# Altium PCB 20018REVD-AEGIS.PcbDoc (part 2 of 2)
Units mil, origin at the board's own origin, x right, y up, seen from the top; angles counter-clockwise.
Board outline 3400 x 2150 mil, 4 copper layers (Top Layer, Signal Layer 1, Signal Layer 2, Bottom Layer), stack 66.258 mil thick; 182 components, 126 nets, 668 pads, 320 vias.

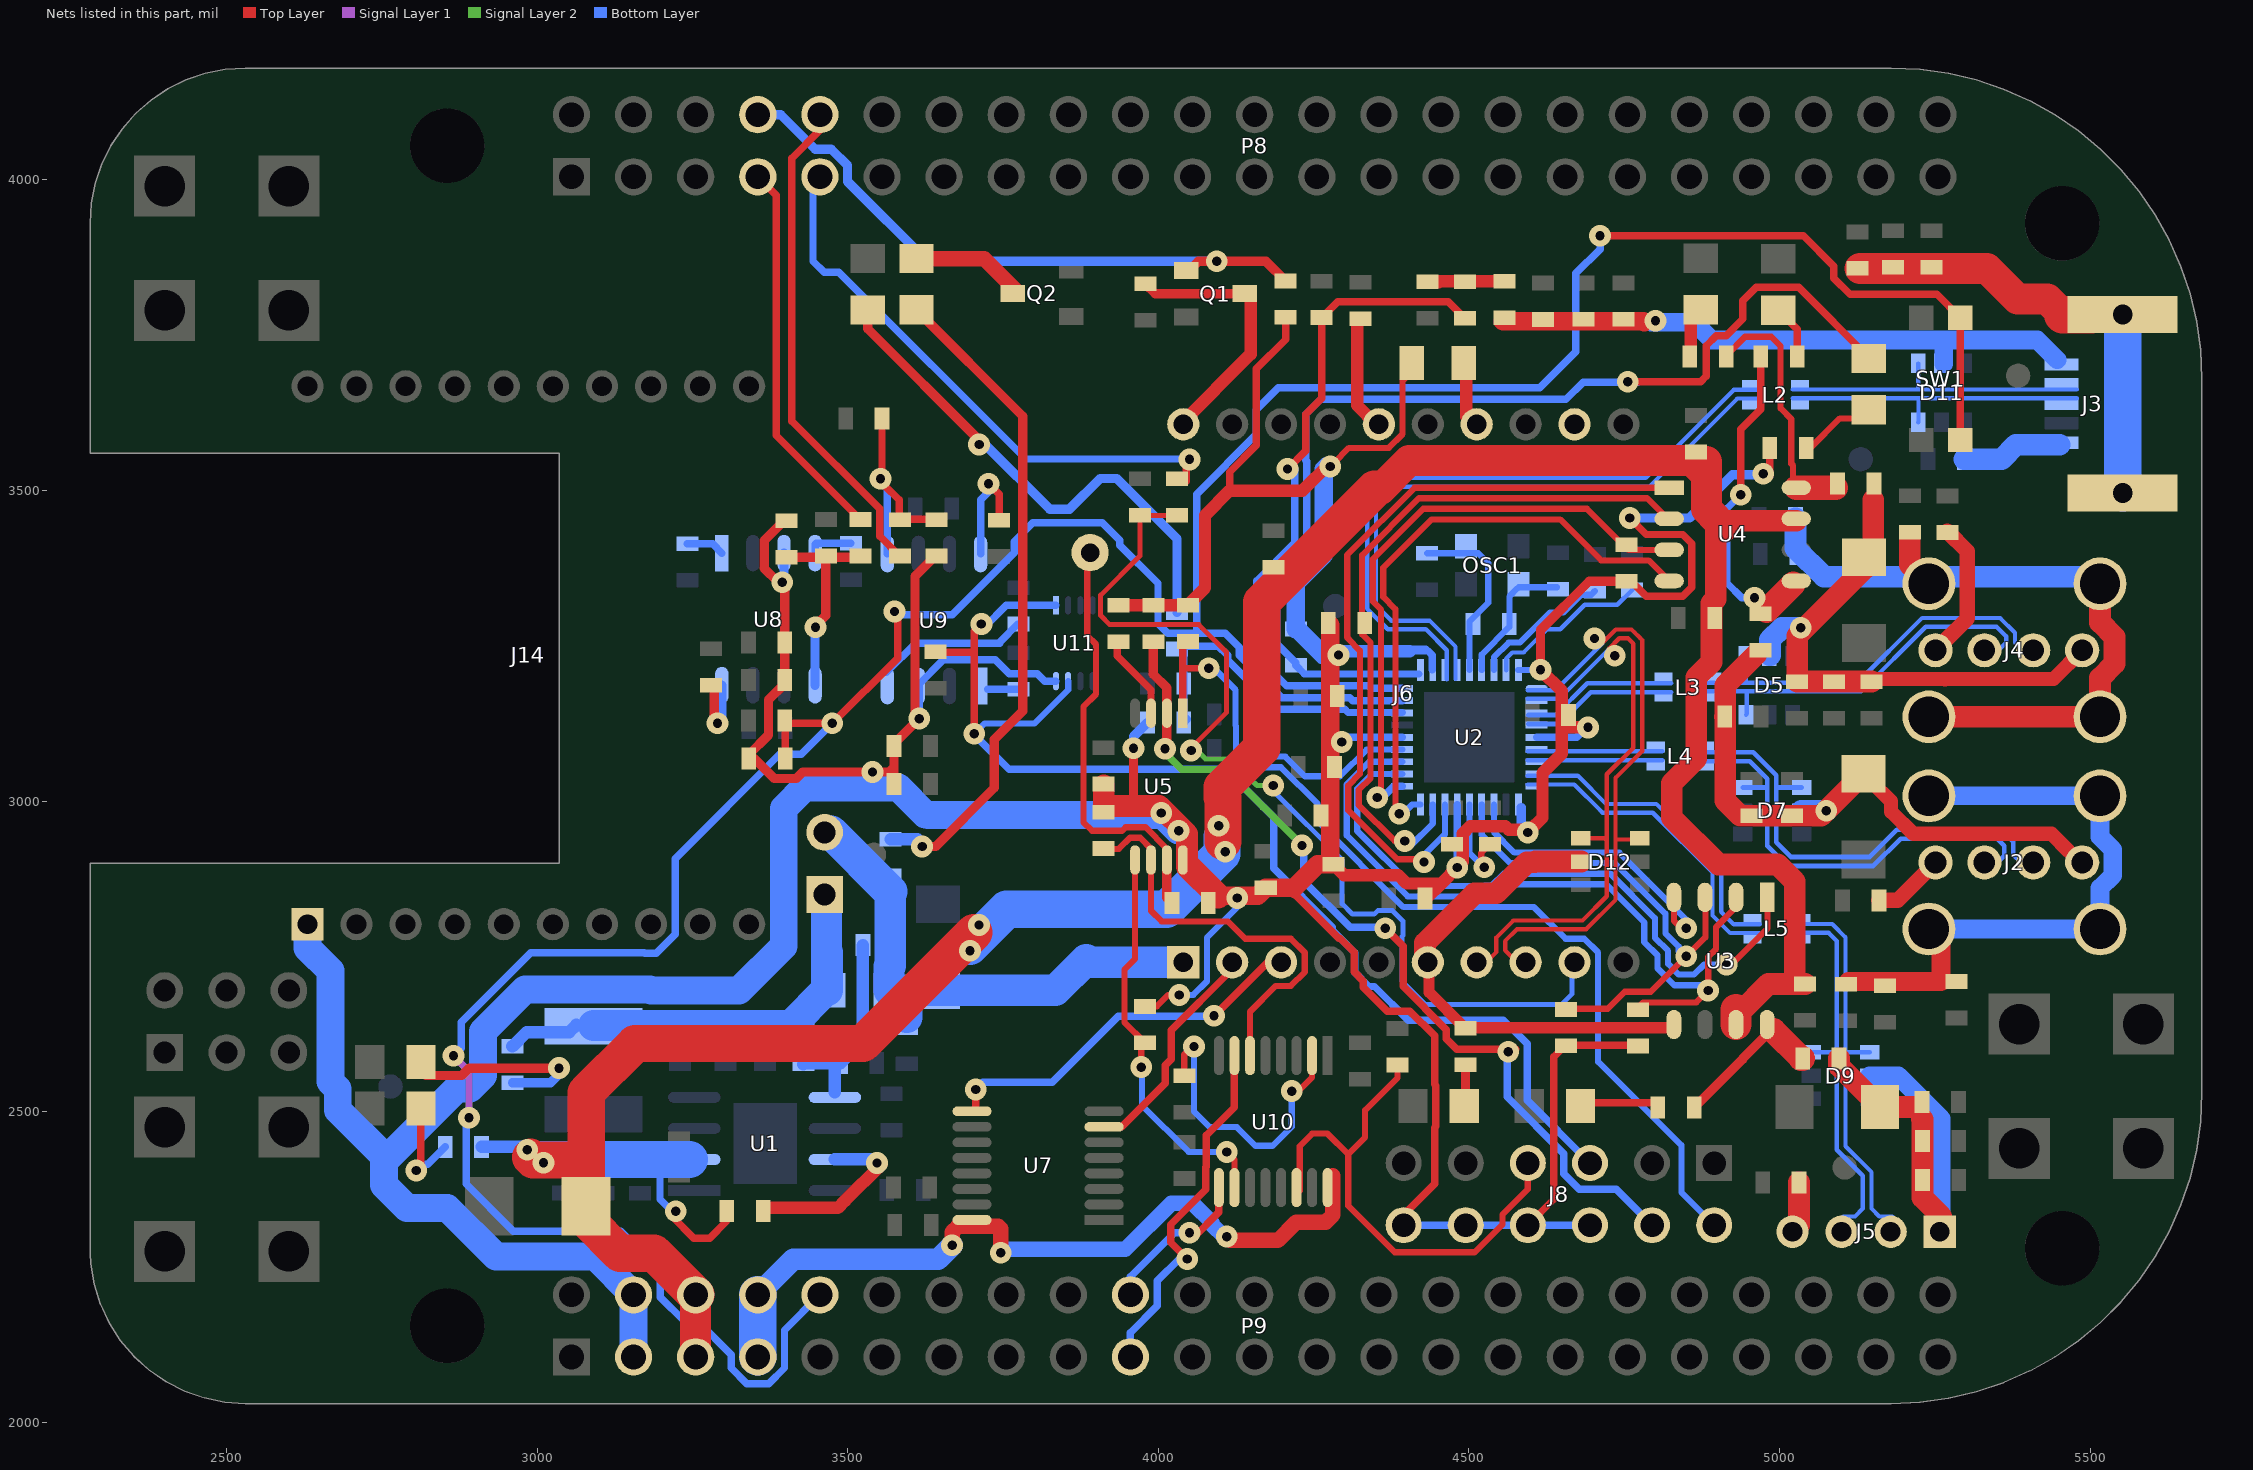
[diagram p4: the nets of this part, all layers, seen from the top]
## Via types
v1: diameter 35, hole 15, Top Layer to Bottom Layer, 320 vias

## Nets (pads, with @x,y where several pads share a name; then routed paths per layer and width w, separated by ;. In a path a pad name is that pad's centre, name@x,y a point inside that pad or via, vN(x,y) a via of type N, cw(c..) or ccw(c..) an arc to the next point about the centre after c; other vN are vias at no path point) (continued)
NetC7_2: C7.2 R5.1 R6.2 U1.5 | length 303.6
  Bottom Layer w20: C7.2@3428.31,2576.21 3430.08,2577.98 3479.22,2577.98 U1.5@3479.22,2530.92 ; R6.2@3488.09,2577.98 3523.88,2613.78 3523.88,2767.32 R5.1@3524.41,2767.85
NetC12_1: C12.1 U2.34 | length 227.7
  Bottom Layer w10: U2.34@4540.09,3210.78 4540.09,3231.41 4563.68,3255 4582.07,3255 4630.4,3303.33 4651.87,3303.33 4680.6,3332.06 4696.73,3332.06 C12.1@4702.89,3338.23
NetC13_1: C13.1 U2.14 | length 145.9
  Top Layer w10: v1@4519.61,2899.36 4519.61,2916.44 C13.1@4533.76,2930.58
  Bottom Layer w10: U2.14@4500.72,2994.25 4500.72,2916.53 v1@4522.72,2894.53
  other v1: 4524.79,2893.49
NetC14_2: C14.2 OSC1.1 R40.2 U2.33 | length 219.8
  Bottom Layer w10: U2.33@4520.4,3210.78 4520.4,3235.77 4565.04,3280.4 4565.04,3329.27 4578.08,3342.31 4580.03,3344.26 C14.2@4641.64,3344.26
NetC15_1: C15.1 FB9.2 J3.6 R19.2 | length 690.1
  Top Layer w50: C15.1@5129.88,3857.56 5333.83,3857.56 5383.4,3808 5431.04,3808 5456.13,3782.91
  Top Layer w60: 5456.13,3782.91 J3.6@5501.66,3782.91
  Bottom Layer w60: J3.6@5552.5,3496.03 J3.6@5552.5,3783.43
NetC16_2: C16.2 OSC1.3 R40.1 U2.32 | length 289.5
  Bottom Layer w10: C16.2@4432.71,3399 4432.86,3398.85 4514.88,3398.85 4531.01,3382.72 4531.01,3319.28 4500.72,3288.99 U2.32@4500.72,3210.78
NetC17_1: C17.1 P9.10 R55.1 SW1.1 SW1.3 U2.26 | length 5392.3
  Top Layer w12: C17.1@3398.62,3130 3399.17,3129.45 R55.1@3399.17,3068.43 ; C17.1@3403.62,3125 v1(3475,3125) 3580,3230 v1@3580,3305 ; v1@4713.71,3910.42 5038.04,3910.42 5087.26,3861.2 5087.26,3841.82 5113.47,3815.61 5253.46,3815.61 SW1.3@5290.97,3778.11 SW1.1@5290.97,3581.26
  Signal Layer 1 w12: v1(2865,2590) 2890,2565 v1(2890,2490)
  Bottom Layer w12: v1(2865,2590) 2877.28,2602.28 2877.28,2643.73 2989.12,2755.58 3172.04,2755.58 3172.62,2755 3191.46,2755 3222,2785.54 3222,2907 3390,3075 3425,3075 v1(3475,3125) ; v1(2890,2490) 2885.48,2485.48 2885.48,2383.41 2961.23,2307.66 3134.01,2307.66 3198,2243.67 3198,2201.19 3237.19,2162 3258.81,2162 3312,2108.81 3312,2087.19 3337.19,2062 3372.81,2062 3398,2087.19 3398,2148 P9.10@3455,2205 ; v1@3575,3300 3668.33,3300 3767.74,3399.41 3767.74,3417.74 3798,3448 3909.88,3448 3938,3419.88 3938,3412 3999.28,3350.72 3999.28,3285.72 4015,3270 4061.46,3270 ; U2.26@4392.45,3161.57 4313,3161.57 4308.07,3166.5 4198.35,3166.5 4130.33,3234.52 4130.33,3247.59 4107.91,3270 4061.46,3270 ; v1(4711.07,3909.94) 4711.07,3888.63 4671.81,3849.38 4671.81,3723.53 4613.92,3665.64 4193.21,3665.64 4157.74,3630.17 4157.74,3590.36 4061.46,3494.08 4061.46,3270
  other v1: 3575,3305
NetC36_1: C36.1 FB11.2 J4.5 R31.2 | length 1145.2
  Top Layer w35: FB11.2@5209.81,3426.7 5209.81,3380.39 J4.5@5240.41,3349.8 ; J4.5@5240.41,3135.62 J4.5@5516,3135.62 5516,3197.91 5539.26,3221.17 5539.26,3264.25 5516,3287.51 J4.5@5516,3349.8
  Bottom Layer w35: R31.2@5025.67,3455.42 5025.67,3407.01 5071.67,3361.01 J4.5@5504.78,3361.01
NetC37_1: C37.1 FB12.2 J2.5 R32.2 | length 1024.2
  Top Layer w30: C37.1@5111.12,2709.35 5260,2709.35 5260,2774.45 J2.5@5240.41,2794.04
  Bottom Layer w30: J2.5@5240.41,2794.04 J2.5@5516,2794.04 5516,2859.86 5536.76,2880.62 5536.76,2921.63 5516,2942.39 J2.5@5516,3008.21 J2.5@5240.41,3008.21
NetD2_1: D2.1 R1.1 | length 146.5
  Top Layer w12: v1(2805,2405) 2812.68,2412.68 D2.1@2812.68,2505
  Bottom Layer w12: 2820,2415 2823.53,2415 R1.1@2851.67,2443.14
NetD3_1: D3.1 R2.1 | length 342
  Top Layer w15: D3.1@2812.68,2580 2820.75,2580 2820.75,2558 2878.25,2558 2890.25,2570 v1@3040,2570
  Bottom Layer w15: R2.1@2960,2546.38 3021.38,2546.38 v1@3040,2565
  other v1: 3035,2570
NetD4_1: D4.1 R9.2 | length 126.3
  Top Layer w10: R9.2@5042.79,3568.55 5049.86,3568.55 5097.28,3615.97 5129.96,3615.97 D4.1@5143.71,3629.72
NetD4_2: D4.2 R10.2 U2.28 | length 1742.2
  Top Layer w12: v1(4755.82,3675.19) 4872.92,3675.19 4881.66,3683.93 4881.66,3732.64 4898.28,3749.26 4914.28,3749.26 4941.07,3776.04 4941.07,3805.59 4962.35,3826.87 5030.89,3826.87 5143.71,3714.05 D4.2@5143.71,3712.4
  Bottom Layer w12: U2.28@4419.53,3204.5 4235.13,3204.5 R10.2@4221.26,3218.38 4221.26,3222.33 4190.54,3253.05 4190.54,3359.96 4238.46,3407.88 4238.46,3547.15 4237.22,3548.39 4237.22,3622.67 4261.19,3646.64 4656.18,3646.64 4683.98,3674.44 v1@4771.64,3674.44
NetD6_1: D6.1 R16.1 | length 126.9
  Top Layer w12: D6.1@4680.4,2514.28 4796.45,2514.28 R16.1@4804.14,2506.59
NetD8_1: D8.1 R17.1 | length 65.4
  Top Layer w15: D8.1@4492.54,2510.97 4494.4,2512.83 R17.1@4494.4,2575.62
NetD10_1: D10.1 R18.1 | length 79.3
  Top Layer w20: R18.1@4856.85,3718.54 4856.85,3774.93 D10.1@4873.04,3791.12
NetD12_5: D12.5 J6.6 R17.2 U3.5 | length 789.1
  Top Layer w18: J6.6@4435.4,2724.46 4435.4,2692.23 4492.62,2635 4824.81,2635 U3.5@4829.95,2640.14
  Top Layer w35: J6.6@4429.37,2740.37 4429.37,2771.88 4508.98,2851.49 4543.6,2851.49 4593.41,2901.3 4606.02,2901.3 4607.19,2902.46 D12.5@4680.22,2902.46
NetD13_1: D13.1 R20.1 | length 85.2
  Top Layer w12: D13.1@4997.94,3790.25 5028.48,3759.72 R20.1@5028.48,3717.72
NetD14_1: D14.1 R21.1 | length 1058
  Top Layer w15: D14.1@3610.69,3790.68 3781.73,3619.63 3781.73,3144.87 3735.81,3098.95 3735.81,3021.19 3641.41,2926.78 v1(3619.52,2926.78)
  Bottom Layer w20: R21.1@3568.84,2938.42 v1@3612.08,2938.42
NetD14_2: D14.2 Q2.2 | length 178.7
  Top Layer w25: D14.2@3610.69,3873.35 3719.18,3873.35 Q2.2@3768.84,3823.7
NetD16_1: D16.1 R38.2 | length 832.1
  Top Layer w15: D16.1@3532.15,3790.65 3532.15,3760.26 3711.3,3581.12 v1(3711.3,3574.11)
  Bottom Layer w15: v1(3711.3,3574.11) 3720.97,3574.11 3825.09,3470 3856.9,3470 3906.27,3519.37 3932.78,3519.37 4030,3422.14 R38.2@4030,3303.37
NetFB2_2: FB2.2 J3.5 | length 162.7
  Bottom Layer w35: FB2.2@5297.61,3550.32 5357.58,3550.32 5380.65,3573.39 J3.5@5450.73,3573.39
NetFB4_2: FB4.2 J5.4 | length 83.7
  Top Layer w35: J5.4@5020.88,2306.54 5031.36,2317.02 FB4.2@5031.36,2385.95
NetFB6_2: FB6.2 J4.4 | length 226.2
  Top Layer w25: J4.4@5251.04,3242.71 5302.41,3294.08 5302.41,3401.76 FB6.2@5269.94,3434.23
NetFB8_2: FB8.2 J2.4 | length 124
  Top Layer w25: FB8.2@5160,2840 5189.91,2840 J2.4@5251.04,2901.13 J2.4@5251.04,2908.75
NetJ6_2: J6.2 U7.7 | length 365.2
  Top Layer w12: U7.7@3912.48,2475.47 3940.87,2475.47 4011.01,2545.61 4011.01,2574.75 4020.5,2584.24 4020.5,2630.76 4114.41,2724.67 J6.2@4114.41,2740.37
NetJ6_3: J6.3 U7.9 | length 618.6
  Top Layer w12: U7.9@3699.88,2500.47 3705.88,2506.46 v1(3705.88,2535.6) ; v1(4089.61,2654.16) 4175.82,2740.37 J6.3@4193.15,2740.37
  Bottom Layer w12: v1(3705.88,2535.6) 3717.38,2547.1 3829.25,2547.1 3935.44,2653.28 v1@4098.84,2653.28
NetJ6_9: J6.9 R24.2 R49.2 | length 1615.2
  Top Layer w8: R49.2@4030,3460 R24.2@3970,3460 3970,3394.41 3906.93,3331.34 3906.93,3298.6 3921.56,3283.97 4065.2,3283.97 4109.35,3239.81 4109.35,3142.28 v1@4046.54,3079.46 ; v1@4048.52,3081.44 v1(4052.61,3081.44)
  Signal Layer 2 w8: v1(4052.61,3081.44) 4062.28,3081.44 4076,3067.73 4115.91,3067.73 4158.64,3025 v1(4185,3025)
  Bottom Layer w8: v1(4185,3025) 4185,3016.09 4295.86,2905.23 4295.86,2834.47 4312.56,2817.77 4347.47,2817.77 4353.19,2823.5 4376.81,2823.5 4393.5,2806.8 4393.5,2783.2 4392.37,2782.07 4392.37,2710.09 4430.27,2672.19 4648.73,2672.19 4665.59,2689.05 J6.9@4665.59,2740.37
NetJ6_12: J6.12
NetJ6_16: J6.16 R22.1 | length 182.6
  Top Layer w20: R22.1@4320,3776.38 4320,3637.14 J6.16@4350.63,3606.51
NetJ8_3: J8.3 R42.1 U11.1 U11.7 | length 1970.1
  Top Layer w12: R42.1@3640.73,3240.13 3641.18,3239.68 3703.54,3239.68 ; v1(3703.54,3108.44) 3703.54,3239.68 ; v1(3715,3285) 3703.54,3273.54 3703.54,3239.68
  Bottom Layer w10: v1(3703.54,3108.44) 3720.1,3125 3800.65,3125 3841.84,3166.19 3842.01,3166.19 3851.92,3176.1 3851.92,3176.27 3854.68,3179.04 U11.7@3854.68,3192.95
  Bottom Layer w12: v1(3703.54,3108.44) 3703.54,3106.84 3759.44,3050.94 4065.46,3050.94 4065.71,3051.2 4107.98,3051.2 4135.47,3023.71 4135.84,3023.71 4183.29,2976.26 4183.29,2975.89 4185.5,2973.68 4185.5,2891.61 4279.99,2797.12 4279.99,2791.76 4315.96,2755.79 4315.96,2724.22 4338.81,2701.37 4347.83,2701.37 4402.07,2647.13 4555.56,2647.13 4593.65,2609.04 4593.65,2518.22 J8.3@4694.78,2417.09 ; v1@3720,3280 3755,3315 U11.1@3835,3315
NetJ8_4: J8.4 R54.2 U10.14 | length 852.6
  Top Layer w10: U10.14@4222.42,2377.54 4227.55,2372.42 4227.55,2444.27 4247.78,2464.5 4272.22,2464.5 4305.55,2431.17 ; R54.2@4385,2575 4385,2554.26 4332.73,2501.99 4332.73,2458.36 4305.55,2431.17 ; J8.4@4594.78,2417.09 4594.78,2375.08 4553.78,2334.08 4553.78,2318.11 4509.03,2273.36 4380.53,2273.36 4305.55,2348.34 4305.55,2431.17
NetJ8_7: J8.7 R35.1 U5.1 | length 1574.4
  Top Layer w10: 4039.25,3213.4 4039.76,3213.91 v1(4080.85,3213.91)
  Top Layer w12: U5.1@4039.25,3141.34 4039.25,3213.4 4039.25,3248.78 R35.1@4047.28,3256.81
  Bottom Layer w10: v1@4087.88,3215.19 4124.29,3178.77 4124.29,3121.47 4124.77,3120.99 4124.77,3074.04 ; 4124.8,3074 4124.8,3059.83 4131.83,3052.8 4165.4,3052.8 4167.09,3054.5 4197.22,3054.5 4256.2,2995.52 4256.2,2967.52 4394.4,2829.32 4604.66,2829.32 4655.61,2778.37 4685.66,2778.37 4707.92,2756.11 4707.92,2579.9 4842.11,2445.71 4842.11,2369.76 J8.7@4894.78,2317.09
NetJ8_8: J8.8 R36.1 U5.2 | length 1426.7
  Top Layer w12: v1(4365,2795) 4393.96,2766.04 4393.96,2701.64 4463.68,2631.91 4463.68,2617.04 4480.3,2600.43 v1@4574.99,2600.43
  Top Layer w15: R36.1@3991.69,3256.51 3991.69,3204.21 4013.66,3182.25 U5.2@4013.66,3141.34 v1@4013.66,3093.86
  Signal Layer 2 w12: v1(4010.61,3084.23) 4010.61,3077.91 4037.8,3050.73 4108.87,3050.73 4150.92,3008.67 4150.92,3008.18 4168.79,2990.31 4169.29,2990.31 v1(4231.14,2928.46)
  Bottom Layer w12: v1(4231.14,2928.46) 4234.11,2925.49 4234.11,2871.02 4308.55,2796.58 4363.42,2796.58 v1(4365,2795) ; v1@4561.56,2593.53 4561.56,2523.44 4652.78,2432.22 4652.78,2399.7 4677.38,2375.09 4736.78,2375.09 J8.8@4794.78,2317.09
  other v1: 4563.15,2596.41
NetP8_7: P8.7 R46.1 | length 620.3
  Top Layer w12: P8.7@3355,4005 3385,3975 3385,3588.53 R46.1@3520.37,3453.16
NetP8_8: P8.8 Q1.1 R48.1 | length 1033.5
  Top Layer w15: Q1.1@4044.29,3848.98 4064.09,3868.78 4173.31,3868.78 R48.1@4204.83,3837.26
  Bottom Layer w15: P8.8@3355,4105 3392.07,4105 3447.57,4049.5 3473.43,4049.5 3499.5,4023.43 3499.5,3997.57 3628.03,3869.03 v1(4093.81,3869.03)
NetP8_9: P8.9 R49.1 | length 916.9
  Top Layer w12: R49.1@4045,3515 v1@4045,3553.41
  Bottom Layer w12: P8.9@3455,4005 3443.84,3993.84 3443.84,3869.18 3461.71,3851.31 3485.55,3851.31 3786.18,3550.68 v1@4050,3550.68
  other v1: 4050,3550
NetP8_10: P8.10 R28.2 | length 800.3
  Top Layer w12: P8.10@3455,4105 3455,4080 3410,4035 3410,3611.44 3551.09,3470.35 3551.09,3426.62 R28.2@3582.8,3394.91
NetP9_19: P9.19 U10.7 | length 584.6
  Top Layer w10: U10.7@4122.42,2575.74 U10.7@4122.42,2590.14
  Top Layer w12: v1(4046.5,2262.6) 4019.5,2289.6 4019.5,2317.63 4076.55,2374.68 4076.55,2410.62 4077.35,2411.43 4077.35,2461.95 4122.42,2507.02 U10.7@4122.42,2575.74
  Bottom Layer w12: P9.19@3955,2105 3955,2144.19 3998,2187.19 3998,2227.32 4033.28,2262.6 v1(4046.5,2262.6)
NetP9_20: P9.20 U10.9 | length 260.8
  Top Layer w12: v1(4050,2305) 4050,2304.67 4057.24,2297.43 4097.42,2337.61 U10.9@4097.42,2377.54
  Bottom Layer w12: P9.20@3955,2205 3955,2234.18 4025.82,2305 v1(4050,2305)
NetR3_1: R3.1 U1.7 | length 287.9
  Top Layer w20: R3.1@3363.62,2345 3483.9,2345 3495.49,2356.59 v1@3553.99,2415.09
  Bottom Layer w20: U1.7@3479.22,2422.92 3540.29,2422.92 v1@3545.53,2417.69
  other v1: 3546.96,2417.23
NetR11_1: R11.1 U5.6 U10.6 | length 689.4
  Top Layer w10: R11.1@3905.33,2922.95 3936.45,2922.95 3954.25,2940.74 3970.71,2940.74 3988.07,2923.38 U5.6@3988.07,2905.12 3988.07,2823.21 4005.08,2806.2 4111.9,2806.2 4139.73,2778.37 4213.22,2778.37 4235.48,2756.11 4235.48,2724.63 4213.22,2702.37 4188.81,2702.37 4147.42,2660.99 U10.6@4147.42,2590.14
NetR12_1: R12.1 U5.5 U10.10 | length 648.9
  Top Layer w10: U5.5@3962.48,2905.12 3962.48,2745.86 3945.2,2728.58 3945.2,2643.87 R12.1@3978.41,2610.66 3972.46,2604.71 v1(3972.46,2571.62) ; v1(4110,2435) 4122.42,2422.58 U10.10@4122.42,2377.54
  Bottom Layer w10: v1(3972.46,2571.62) 3973.34,2570.73 3973.34,2510.49 4048.83,2435 v1(4110,2435)
NetR15_2: R15.2 U2.35 | length 267.1
  Bottom Layer w7: U2.35@4559.77,3210.78 4559.77,3229.18 4569.6,3239 4587.99,3239 4625.63,3276.65 4647.1,3276.65 4686.38,3315.92 4738.86,3315.92 R15.2@4762.7,3339.76
NetR25_1: R25.1 R28.1 R45.2 U9.5 | length 324.3
  Top Layer w12: v1(3552.6,3518.66) 3554.99,3521.05 R45.2@3554.99,3615.71 ; v1@3558.89,3508.61 3582.8,3484.69 3582.8,3453.53 R25.1@3634.21,3453.53
  Bottom Layer w12: v1@3560.13,3506.11 3563.66,3502.58 U9.5@3563.66,3397.72
NetR30_1: R30.1 U8.8 | length 117.8
  Top Layer w15: R30.1@3285,3176.21 3285,3130 v1(3290,3125)
  Bottom Layer w15: v1(3290,3125) 3297.19,3132.19 U8.8@3297.19,3186.55
NetR34_1: R34.1 TP1.1 U5.7 | length 697.7
  Top Layer w10: TP1.1@3890,3400 3885.42,3395.42 3885.42,3266.3 3899.5,3252.22 3899.5,3172.13 3879.29,3151.92 3879.29,2965.89 3893.11,2952.07 3941.54,2952.07 3947.2,2957.74 3979.3,2957.74 4013.66,2923.38 U5.7@4013.66,2905.12
  Top Layer w15: U5.7@4013.66,2905.12 4013.66,2844.12 R34.1@4021.86,2835.92
NetR37_1: R37.1 U5.3 | length 137.8
  Top Layer w12: R37.1@3933.45,3256.52 3933.45,3233.47 3988.07,3178.85 U5.3@3988.07,3141.34
NetR39_2: R39.2 U9.8 | length 173.7
  Top Layer w12: v1(3726.48,3510.7) 3743.53,3493.66 R39.2@3743.53,3452.2
  Bottom Layer w12: U9.8@3713.66,3397.72 3713.66,3485.31 v1@3728.16,3499.81
NetR41_1: R41.1 R46.2 R47.2 U8.5 | length 326.5
  Top Layer w15: R41.1@3402.25,3392.46 R47.2@3464.59,3392.46 ; v1@3451.78,3285.81 3464.59,3298.62 R47.2@3464.59,3392.46 ; R47.2@3464.59,3394.53 R47.2@3464.59,3392.46 ; R46.2@3520.37,3394.54 3518.29,3392.46 R47.2@3464.59,3392.46
  Bottom Layer w15: U8.5@3447.19,3186.55 3447.19,3278.78 v1(3448.04,3279.64)
NetR44_1: R44.1 U10.2 | length 488.1
  Top Layer w10: R44.1@4041.73,2557.55 4041.73,2592.07 v1@4057.16,2607.51 ; v1(4214.55,2532.97) 4225.04,2532.97 4247.42,2555.36 U10.2@4247.42,2590.14
  Bottom Layer w10: v1(4057.16,2604.64) 4057.16,2500.19 4082.28,2475.07 4125.99,2475.07 4156.13,2444.92 4183.86,2444.92 4214.55,2475.61 v1(4214.55,2532.97)
NetR59_2: R59.2 U9.1 | length 50
  Bottom Layer w12: 3725,3180 R59.2@3775,3180
NetR60_2: R60.2 U9.4 | length 246.4
  Bottom Layer w12: U9.4@3561.89,3206.89 3609.28,3254.28 3744.28,3254.28 3744.28,3255.82 3773.47,3285 R60.2@3775,3285
NetR61_2: R61.2 U8.1 | length 61.8
  Bottom Layer w12: R61.2@3241.52,3413.96 3282.37,3413.96 U8.1@3297.19,3399.15
NetR62_2: R62.2 U8.4 | length 72.5
  Bottom Layer w12: U8.4@3447.19,3399.15 3447.19,3413.09 3449.09,3415 R62.2@3505,3415
NON_REM1: R13.1 U2.22 | length 280.5
  Bottom Layer w10: R13.1@4148.1,3083.79 R13.1@4149,3082.9 ; R13.1@4148.61,3082.52 4159.63,3071.5 4204.26,3071.5 4235.76,3040 4292.25,3040 4335.08,3082.83 U2.22@4392.45,3082.83
OCS1: R51.1 U2.13 U3.3 | length 788.9
  Top Layer w10: R51.1@4655.32,2665.4 4723.42,2665.4 4750.78,2692.76 4792.76,2692.76 v1(4850,2750) 4880.67,2780.67 U3.3@4880.67,2830.01
  Bottom Layer w10: U2.13@4520.4,2994.25 4520.4,2945.76 4566.16,2900 4734.87,2900 4816.33,2818.54 4816.33,2786.95 4837.56,2765.72 v1@4837.56,2758.02
OCS2: R52.1 U2.17 U4.2 | length 1153.5
  Top Layer w10: v1(4396.78,2935.69) 4380.35,2935.69 4322.66,2993.39 4322.66,3017.83 4341.5,3036.66 4341.5,3255.02 4327.95,3268.57 4327.95,3396.03 4419.38,3487.46 4786.7,3487.46 4819.85,3454.31 U4.2@4822.25,3454.31
  Bottom Layer w10: v1@4395,2935 4402.07,2935 4407.48,2929.59 4441.66,2963.76 U2.17@4441.66,2994.25
OCS3: R53.1 U2.19 U4.3 | length 989.7
  Top Layer w10: v1(4352.16,3005.61) 4358.5,3011.95 4358.5,3307.91 4344.95,3321.46 4344.95,3388.99 4426.42,3470.46 4689.91,3470.46 4748.69,3411.68 4749.52,3411.68 4756.89,3404.31 U4.3@4822.25,3404.31
  Bottom Layer w12: v1(4352.16,3005.61) 4352.16,2997.23 4378.71,3023.78 U2.19@4392.45,3023.78
OCS4: R50.1 U2.21 U3.2 | length 1200.9
  Top Layer w10: R50.1@4769.41,2664.89 4780.28,2675.76 4865.76,2675.76 v1(4885,2695) 4885.15,2695.15 4885.15,2749.01 4897.67,2761.52 4897.67,2797.01 U3.2@4930.67,2830.01
  Bottom Layer w10: U2.21@4392.45,3063.15 4339.44,3063.15 4303.08,3026.78 4303.08,2944.68 4401.41,2846.35 4543.41,2846.35 4563.06,2866 4720.79,2866 4782.33,2804.46 4782.33,2772.87 4803.5,2751.7 4803.5,2730.74 4830.74,2703.5 4876.5,2703.5 v1(4885,2695)
PRTPWR1: U2.12 U3.4 | length 489.1
  Top Layer w10: U3.4@4829.95,2844.86 4829.95,2807.36 4842.31,2795 v1(4850,2795)
  Bottom Layer w10: U2.12@4540.09,2994.25 4540.09,2950.12 4573.2,2917 4741.91,2917 4850,2808.91 v1(4850,2795)
PRTPWR2: U2.16 U4.1 | length 1239.2
  Top Layer w10: v1(4427.47,2901.74) 4423.02,2906.19 4384.56,2906.19 4305.66,2985.1 4305.66,3024.87 4324.5,3043.71 4324.5,3242.22 4305.47,3261.25 4305.47,3262.12 4304.14,3263.46 4304.14,3396.26 4412.34,3504.46 4822.1,3504.46 U4.1@4822.25,3504.31
  Bottom Layer w10: v1@4429.86,2914.81 4461.35,2946.29 U2.16@4461.35,2994.25
PRTPWR3: U2.18 U4.4 | length 979.3
  Top Layer w10: v1(4387.77,2979.4) 4381.66,2985.51 4381.66,3308.79 4361.95,3328.51 4361.95,3375.69 4439.72,3453.46 4646.64,3453.46 4712.79,3387.31 4789.25,3387.31 U4.4@4822.25,3354.31
  Bottom Layer w10: v1@4390.6,2976.57 4408.28,2994.25 U2.18@4421.98,2994.25
PRTPWR4: U2.20 U3.1 | length 1009.6
  Top Layer w10: v1@4923.81,2738.03 4980.67,2794.89 U3.1@4980.67,2830.01
  Bottom Layer w10: U2.20@4392.45,3043.46 4343.8,3043.46 4320.08,3019.74 4320.08,2951.73 4408.45,2863.35 4524.8,2863.35 ; 4524.8,2863.99 4537.01,2863.99 4556.02,2883 4727.83,2883 4799.33,2811.5 4799.33,2779.91 4820.5,2758.74 4820.5,2737.78 4837.78,2720.5 4862.22,2720.5 4878.51,2736.79 v1(4914.65,2736.79)
SKY_ONOFF: J6.20 Q1.2 R63.2 | length 409.2
  Top Layer w15: R63.2@3979.33,3832.58 3995.01,3816.9 Q1.2@4139.04,3816.9
  Top Layer w20: J6.20@4035.67,3606.51 4148.51,3719.35 4148.51,3802.76
SKY_USBD-_N: D12.3 J6.8 U2.1 | length 966
  Top Layer w7: J6.8@4591.18,2740.37 4577.62,2740.37 4558.15,2759.85 4558.15,2774.44 4577.3,2793.59 4688.61,2793.59 4735.84,2840.82 4735.84,2937.96 ; v1@4715.7,3255.6 4736.25,3276.16 4761.71,3276.16 4765.81,3272.06 4775.17,3262.69 4778.69,3259.17 4778.69,3080.09 4735.84,3037.24 4735.84,2937.96 ; D12.3@4774.71,2939.86 4772.81,2937.96 4735.84,2937.96
  Bottom Layer w7: U2.1@4594.81,3178.41 4608.98,3178.41 4639.29,3178.41 4712.41,3251.53 v1@4714.52,3253.64
  other v1: 4702.21,3261.74
SKY_USBD-_P: D12.4 J6.7 U2.2 | length 953.3
  Top Layer w7: J6.7@4508.11,2740.37 J6.7@4512.44,2740.37 4527.62,2740.37 4544.15,2756.9 4544.15,2780.24 4571.5,2807.59 4682.81,2807.59 4721.84,2846.62 4721.84,2936.7 ; D12.4@4680.22,2939.86 4718.68,2939.86 4721.84,2936.7 ; v1@4725.6,3245.7 4742.05,3262.16 4755.91,3262.16 4764.69,3253.37 4764.69,3085.89 4721.84,3043.03 4721.84,2936.7
  Bottom Layer w7: U2.2@4594.29,3164.41 4608.98,3164.41 4645.09,3164.41 4724.57,3243.9 v1@4725.75,3245.08
  other v1: 4734.61,3233.86
SKY_VR: J6.14 R23.1 | length 104.9
  Top Layer w20: R23.1@4495.66,3706.22 4495.66,3618.96 J6.14@4508.11,3606.51
USB_F_P2_N: D5.4 J4.2 L3.1 | length 645.9
  Bottom Layer w7: L3.1@4880.22,3190.46 4892.03,3190.46 4947.58,3190.46 ; D5.4@4946.03,3233.49 4946.03,3192 4947.58,3190.46 ; J4.2@5408.52,3242.71 5391.29,3242.71 5379,3255 5379,3270.8 5355.09,3294.71 5229.5,3294.71 5125.25,3190.46 4947.58,3190.46
USB_F_P2_P: D5.3 J4.3 L3.2 | length 622.8
  Bottom Layer w7: L3.2@4880.22,3176.46 4892.03,3176.46 4947.33,3176.46 ; D5.3@4946.03,3139 4947.33,3140.29 4947.33,3176.46 ; J4.3@5329.78,3242.71 5352.71,3242.71 5365,3255 5365,3265 5349.29,3280.71 5235.3,3280.71 5131.05,3176.46 4947.33,3176.46
USB_F_P4_N: D9.4 J5.2 L5.1 | length 623.3
  Bottom Layer w7: L5.1@5023.61,2801.94 5035.27,2801.94 5084.8,2801.94 5106.26,2780.49 5106.26,2594.73 ; D9.4@5145.27,2595.29 5106.82,2595.29 5106.26,2594.73 ; J5.2@5181.35,2331.19 5178.88,2331.19 5160.7,2331.19 5148.04,2343.84 5148.04,2402.5 5106.26,2444.28 5106.26,2594.73
USB_F_P4_P: D9.3 J5.3 L5.2 | length 600.8
  Bottom Layer w7: L5.2@5023.61,2787.94 5035.27,2787.94 5079,2787.94 5092.26,2774.69 5092.26,2595.01 ; D9.3@5050.78,2595.29 5091.98,2595.29 5092.26,2595.01 ; J5.3@5102.35,2331.19 5121.39,2331.19 5134.04,2343.84 5134.04,2396.7 5092.26,2438.48 5092.26,2595.01
USB_F_PWR_2: C28.1 C29.1 C40.1 C41.1 D5.5 FB5.2 J4.1 | length 905.9
  Top Layer w23: C40.1@5148.58,3192.3 5152.9,3196.62 5441.17,3196.62 J4.1@5487.26,3242.71 ; 5266.09,3196.21 5266.8,3196.21
  Top Layer w35: C40.1@5148.3,3192.03 5148.3,3192.3 5028.68,3192.3 5028.68,3265.72 5135.93,3372.96 C28.1@5135.93,3392.41 5150.84,3407.32 5150.84,3484.78
  Bottom Layer w35: D5.5@4984.53,3234.58 4984.53,3259.38 5004.13,3278.98 v1(5034.24,3278.98)
USB_F_PWR_3: C48.1 C49.1 C50.1 C51.1 D7.5 FB7.2 J2.1 | length 947.8
  Top Layer w23: C48.1@5148.9,3030 5179.41,2999.49 5179.41,2982.95 5215.14,2947.21 5284.91,2947.21 5285,2947.13 5437.87,2947.13 5465,2920
  Top Layer w24: C48.1@5135,3043.9 C48.1@5148.9,3030
  Top Layer w35: C50.1@4911.65,3135.77 C50.1@4912.63,3135.77 ; FB7.2@4962.28,3236.02 4912.63,3186.38 C50.1@4912.63,3135.77 ; C48.1@5135,3043.9 v1(5075,2984.43) 5066.94,2976.38 C51.1@5020,2976.38 C49.1@4955,2976.38 4936.59,2976.38 4912.63,3000.33 C50.1@4912.63,3135.77
  Bottom Layer w35: D7.5@5035.54,2984.43 v1(5075,2984.43)
USB_F_PWR_4: C44.1 C45.1 C46.1 C47.1 D9.5 FB3.2 J5.1 | length 636.4
  Top Layer w35: FB3.2@5095.83,2585.64 5095.83,2573.18 C44.1@5161.77,2507.24 C45.1@5221.48,2507.24 ; 5229.5,2488.11 5230.31,2487.29 5230.31,2361.23 J5.1@5260.35,2331.19
  Bottom Layer w30: D9.5@5145.27,2557.89 5191.17,2557.89 5260.35,2488.71 J5.1@5260.35,2331.19
USB_HS_IND: R29.1 R33.1 R38.1 U2.25 | length 529.7
  Bottom Layer w12: R38.1@4039.88,3249.37 4096.5,3249.37 4111.33,3234.54 4111.33,3226.65 4190.48,3147.5 4300.2,3147.5 4305.2,3142.5 U2.25@4392.45,3142.5 ; R29.1@4040.58,3125.95 R29.1@4040.9,3126.27 4046.54,3131.91 4040.9,3137.54 R33.1@4040.9,3189.51 R38.1@4040.9,3249.37
USB_P2_N: L3.4 U2.3 | length 251
  Bottom Layer w7.5: U2.3@4595.32,3138.46 4608.98,3138.46 4639.29,3138.46 4690.34,3189.51 4813.29,3189.51 L3.4@4825.14,3189.51
USB_P2_P: L3.3 U2.4 | length 251
  Bottom Layer w7.5: U2.4@4595.32,3123.88 4608.98,3123.88 4645.22,3123.88 4696.35,3175.01 4813.29,3175.01 L3.3@4825.14,3175.01
USB_P3_N: L4.4 U2.6 | length 216.6
  Bottom Layer w7.5: U2.6@4594.56,3080.24 4608.98,3080.24 4800.82,3080.24 L4.4@4811.2,3080.24
USB_P3_P: L4.3 U2.7 | length 216.6
  Bottom Layer w7.5: U2.7@4594.56,3065.74 4608.98,3065.74 4800.82,3065.74 L4.3@4811.2,3065.74
USB_P4_N: L5.4 U2.8 | length 513.3
  Bottom Layer w7: U2.8@4594.56,3040.62 4608.98,3040.62 4675.39,3040.62 4720.76,2995.25 4801.77,2995.25 4906.12,2890.9 4906.12,2821.52 4926.23,2801.41 4956.53,2801.41 L5.4@4968.15,2801.41
USB_P4_P: L5.3 U2.9 | length 513.2
  Bottom Layer w7: U2.9@4594.69,3026.62 4608.98,3026.62 4669.59,3026.62 4710.86,2985.35 4714.96,2981.25 4795.97,2981.25 4892.12,2885.1 4892.12,2815.72 4920.43,2787.41 4956.53,2787.41 L5.3@4968.15,2787.41
USB_PWR_2: FB5.1 R18.2 U4.8 | length 406.2
  Top Layer w10: R18.2@4915.47,3718.54 4944.37,3747.44 4986.64,3747.44 5001.64,3732.43 5001.64,3632.37 5018.98,3615.03 5018.98,3543.09 5021.76,3540.31 5021.76,3509.53 U4.8@5026.98,3504.31
  Top Layer w40: U4.8@5026.98,3504.31 FB5.1@5090.23,3504.31
USB_PWR_3: FB7.1 R20.2 U4.5 | length 533.6
  Top Layer w12: v1(4937.5,3493.11) 4937.5,3598.49 4969.86,3630.86 R20.2@4969.86,3717.72 ; v1(4959.74,3327.1) 4959.74,3322.1 4969.02,3312.82 FB7.1@4969.02,3301.38
  Top Layer w40: FB7.1@4979.34,3306.67 U4.5@5022.13,3349.46
  Bottom Layer w12: v1(4937.5,3493.11) 4915.38,3471 4915.38,3351.06 4939.34,3327.1 v1(4959.74,3327.1)
USB_PWR_4: FB3.1 R16.2 U3.8 | length 233.3
  Top Layer w15: R16.2@4862.76,2506.59 4940.66,2584.48 4940.66,2585.27 U3.8@4980.67,2625.28
  Top Layer w40: U3.8@4990.03,2630.41 5034.8,2585.64 FB3.1@5037.2,2585.64
USB_UP_N: L2.4 U2.30 | length 1084.3
  Bottom Layer w7: U2.30@4464.19,3196.07 4464.19,3210.78 4464.19,3242.84 4430.58,3276.45 4369.17,3276.45 4336.34,3309.28 4336.34,3490.23 4340.44,3494.33 4366.35,3520.25 4784.71,3520.25 4926.39,3661.93 4954.11,3661.93 L2.4@4966.39,3661.93
USB_UP_P: L2.3 U2.31 | length 1060.7
  Bottom Layer w7: U2.31@4478.19,3196.4 4478.19,3210.78 4478.19,3248.63 4436.38,3290.45 4374.96,3290.45 4350.34,3315.08 4350.34,3484.43 4372.15,3506.25 4790.51,3506.25 4932.19,3647.93 4954.11,3647.93 L2.3@4966.39,3647.93
USBL_F_P3_N: D7.4 J2.2 L4.1 | length 764.6
  Bottom Layer w7.5: L4.1@4870.06,3078.25 4879.56,3078.25 4957.79,3078.25 4994.5,3041.55 4994.5,3021.46 ; D7.4@5035.54,3021.84 4994.88,3021.84 4994.5,3021.46 ; J2.2@5408.52,2901.13 5388.82,2901.13 5376.42,2913.52 5376.42,2934.08 5356.63,2953.88 5188.88,2953.88 5144.95,2909.95 5018.24,2909.95 4994.5,2933.69 4994.5,3021.46
USBL_F_P3_P: D7.3 J2.3 L4.2 | length 739.5
  Bottom Layer w7.5: L4.2@4870.06,3063.75 4879.56,3063.75 4951.79,3063.75 4980,3035.54 4980,3021.46 ; D7.3@4941.05,3021.84 4979.62,3021.84 4980,3021.46 ; J2.3@5329.78,2901.13 5351.13,2901.13 5361.92,2911.92 5361.92,2928.08 5350.62,2939.38 5194.88,2939.38 5150.96,2895.45 5012.23,2895.45 4980,2927.68 4980,3021.46
USBL_F_UP_N: D11.4 J3.2 L2.1 | length 498.4
  Bottom Layer w7: L2.1@5021.11,3662.48 5032.85,3662.48 5454.07,3662.48 J3.2@5478.68,3662.48 ; 5223.42,3663.67 D11.4@5223.43,3704.52
USBL_F_UP_P: D11.3 J3.3 L2.2 | length 496.1
  Bottom Layer w7: 5021.11,3648.48 5032.85,3648.48 5223.67,3648.48 ; D11.3@5223.43,3610.03 5223.67,3610.27 5223.67,3648.48 ; J3.3@5478.68,3648.48 5454.07,3648.48 5223.67,3648.48
VBUS_DET: R7.2 R8.2 U2.27 | length 1101.3
  Top Layer w12: v1(4207.9,3534.58) 4237.22,3563.9 4237.22,3622.67 4262.82,3648.27 R8.2@4262.82,3778.44 4288.41,3804.03 4466.68,3804.03 R7.2@4493.22,3777.49
  Bottom Layer w12: v1@4219.46,3534.74 4219.46,3415.75 4158,3354.28 4158,3233.72 4206.22,3185.5 4338.74,3185.5 4342.98,3181.26 U2.27@4392.45,3181.26
VBUS_F_UP: C32.1 C42.1 C43.1 D11.5 FB1.2 J3.1 | length 944.6
  Top Layer w30: FB1.2@4554.86,3772.46 4780.65,3772.46 4782.2,3770.92
  Bottom Layer w30: v1@4793.24,3770.58 4862.63,3770.58 4890.94,3742.27 5264.42,3742.27 ; D11.5@5264.42,3704.26 5264.42,3742.27 ; J3.1@5446.85,3710.29 5414.87,3742.27 5264.42,3742.27
  other v1: 4800.18,3773.18
VBUS_UP: C11.1 FB1.1 R7.1 | length 106.7
  Top Layer w20: 4451.29,3834.85 4453.16,3836.73 FB1.1@4557.2,3836.73
VCC3.3V: C18.1 C19.1 C20.1 C21.1 C22.1 C23.1 C24.1 C25.1 C26.1 C27.1 C30.1 C38.1 C39.1 J8.9 J8.10 J8.11 J8.12 J14.1 P9.3 P9.4 R9.1 R10.1 R11.2 R12.2 R23.2 R25.2 R29.2 R34.2 R35.2 R36.2 R37.2 R41.2 R48.2 R50.2 R51.2 R52.2 R53.2 R55.2 U2.5 U2.10 U2.15 U2.23 U2.29 U2.36 U5.8 U8.3 U9.3 U11.8 | length 10497.9
  Top Layer w10: R12.2@3978.41,2669.28 3997.2,2669.28 4015.66,2687.74 v1(4033.61,2687.74) ; v1(4276.75,3538.58) 4281.96,3543.79 4306.68,3568.51 4370.7,3568.51 4392.96,3590.77 4392.96,3677.01 4411.48,3695.54 R23.2@4411.48,3706.22
  Top Layer w12: 4114.73,3499.73 4114.73,3529.75 4157.74,3572.76 4157.74,3696.06 4204.72,3743.04 4204.72,3778.52 R48.2@4204.83,3778.64 ; 4218.79,2850.75 4290.17,2779.37 4292.37,2779.37 4315.22,2756.53 4315.22,2724.96 4330.03,2710.15 4330.03,2700.18 4368.58,2661.62 4404.91,2661.62 4444.68,2621.85 4444.68,2543.64 4446.49,2541.84 4446.49,2475.96 4444.68,2474.15 4444.68,2383.81 4394.78,2333.9 J8.12@4394.78,2317.09 ; v1@4276.07,3543.79 v1@4281.96,3543.79 ; J8.10@4594.78,2317.09 4636.87,2359.19 4636.87,2384.46 4636.78,2384.55 4636.78,2435.49 4636.47,2435.8 4636.47,2587.93 4655.32,2606.78 4768.9,2606.78 R50.2@4769.41,2606.27 ; v1(4759.05,3455.76) 4785.69,3429.12 4844.34,3429.12 4858.88,3414.59 4858.88,3344.03 4844.34,3329.5 4785.67,3329.5 R53.2@4762.11,3353.06 ; v1@4984.17,3522.65 R9.1@4984.17,3568.55
  Top Layer w15: v1@3388.04,3352.08 3365.15,3374.97 3365.15,3419.19 R41.2@3397.36,3451.41 ; v1(3394.29,3352.08) 3398.62,3347.74 C19.1@3398.62,3255 C18.1@3398.62,3195 ; C18.1@3398.62,3189.38 3372.31,3163.07 3372.31,3106.28 3340.55,3074.52 R55.2@3340.55,3068.43 3349.14,3068.43 3381.36,3036.21 3416.99,3036.21 3427.48,3046.7 v1(3539.69,3046.7) 3566.78,3046.7 3574.34,3054.27 ; C39.1@3574.34,3041.61 3574.34,3054.27 ; R25.2@3641.11,3394.93 3608,3361.82 3608,3139.52 v1(3614.83,3132.69) 3574.34,3092.2 C38.1@3574.34,3088.71 3574.34,3054.27 ; v1(3960,3085) 3960,2999.55 3967.48,2992.07 ; 4218.79,2850.75 4218.79,2860.26 ; v1(4615.18,3211.28) 4615.18,3275.49 4693.64,3353.95 R53.2@4753.9,3353.95 ; R53.2@4753.9,3353.06 R53.2@4762.11,3353.06
  Top Layer w20: R37.2@3943.62,3314.97 4046.81,3314.97 R35.2@4047.28,3315.43 4075,3343.16 4075,3460 4114.73,3499.73 4232,3499.73 v1@4276.07,3543.79 ; C23.1@4281.49,2898.11 4298.83,2880.77 4386.14,2880.77 4399.67,2867.24 4455.42,2867.24 ; C25.1@4429.27,2842.7 4430.88,2842.7 4455.42,2867.24 ; v1(4594.78,2949.45) v1@4599.23,2953.89 ; v1(4615.18,3211.28) 4649.59,3176.87 4649.59,3114.28 ; v1(4691.76,3118.52) 4653.83,3118.52 4649.59,3114.28 ; 4455.42,2867.24 v1(4481.03,2892.85) 4490.29,2902.11 4490.29,2947.76 4501.92,2959.39 4558.52,2959.39 4564.01,2953.89 v1@4599.23,2953.89 ; v1@4599.23,2953.89 4618.34,2973.01 4618.34,3045.1 4649.59,3076.35 4649.59,3114.28
  Top Layer w30: 4096.02,2847.25 4159.8,2847.25 C27.1@4172.8,2860.26 4218.79,2860.26 4256.64,2898.11 C23.1@4281.49,2898.11 4276.77,2902.83 R52.2@4276.77,3283.29
  Top Layer w35: R11.2@3911.96,2992.07 C21.1@3911.96,3025.44 ; R11.2@3915.84,2992.07 3967.48,2992.07 4000.93,2992.07 4046.03,2946.97 U5.8@4046.03,2897.24
  Top Layer w40: 4048.53,2894.74 4096.02,2847.25
  Bottom Layer w10: v1(4033.61,2687.74) 4056.34,2687.74 4078,2709.4 4078,2779.96 4127.07,2829.03 v1(4127.07,2843.93) ; U2.36@4579.46,3210.78 v1@4606.37,3210.78
  Bottom Layer w12: U9.3@3613.66,3185.12 3613.66,3187.52 3653.79,3227.65 3737.35,3227.65 3760,3205 3804.71,3205 3816.76,3192.95 U11.8@3835,3192.95 ; v1(4295,3095) 4302.52,3102.52 U2.23@4392.45,3102.52 ; J8.12@4394.78,2317.09 J8.11@4494.78,2317.09 J8.10@4594.78,2317.09 J8.9@4694.78,2317.09 ; 4432.53,3241.5 4434.48,3241.5 4440.98,3235 U2.29@4440.98,3211.47 ; v1(4481.03,2892.85) U2.15@4481.03,2994.25 ; U2.5@4608.98,3102.52 4673.44,3102.52 v1@4685.6,3114.67
  Bottom Layer w15: v1@3397.19,3352.08 U8.3@3397.19,3399.15 ; U9.3@3613.66,3185.12 3613.66,3133.87 v1(3614.83,3132.69) ; v1(3960,3085) 3960,3103.99 R29.2@3982.28,3126.27 ; 4404.89,3240.97 4406.92,3243 4430.03,3243 ; U2.10@4584.05,2989.65 4584.05,2960.95 v1@4590,2955 ; v1(4759.05,3455.76) 4854.89,3455.76 4924.24,3525.11 4971.85,3525.11 v1(4973.69,3526.95)
  Bottom Layer w20: v1(4290,3235) 4295.97,3240.97 4404.89,3240.97
  Bottom Layer w30: R10.1@4221.26,3277 4221.26,3351.08 4266.46,3396.28 4266.46,3534.19 4270.86,3538.58 v1(4276.75,3538.58) ; R10.1@4223.27,3277 4265.27,3235 v1(4290,3235)
  Bottom Layer w45: J14.1@2630,2801.69 2630,2763.53 2666.77,2726.77 2666.77,2548.38 2678.71,2536.43 2678.71,2502.49 2753,2428.2 ; P9.3@3155,2105 P9.4@3155,2205 3093.45,2266.55 2933.36,2266.55 2855,2344.91 2790.09,2344.91 2753,2382 2753,2419.47 2870.53,2537 2892,2537 2912.78,2557.78 2912.78,2629.03 2980.21,2696.46 3181.41,2696.46 3182.87,2695 3324.92,2695 3396.74,2766.82 3396.74,2988.26 3430.34,3021.86 3581.31,3021.86 3625.25,2977.92 3628.44,2977.92 3628.92,2977.44 4007.29,2977.44 v1(4032.5,2952.23)
  other v1: 4004.64,2980.79
VCC5V: P9.7 P9.8 U7.16 U10.16 | length 1269.7
  Top Layer w25: v1(3667.81,2284.85) 3667.81,2305.96 3677.08,2315.23 ; U7.16@3681.07,2319.22 3677.08,2315.23 ; v1(3745.95,2272.65) 3745.95,2311.72 3742.44,2315.23 3677.08,2315.23 ; v1(4109.85,2298.69) 4116.06,2292.49 4192.49,2292.49 4222,2322 4269.31,2322 4281.05,2333.73 4281.05,2396.29
  Bottom Layer w25: v1(3745.95,2272.65) 3751.27,2277.97 3946.47,2277.97 4020.92,2352.42 4054.9,2352.42 4087,2320.33 4087,2317 4105.31,2298.69 v1(4109.85,2298.69)
  Bottom Layer w35: P9.8@3355,2205 3412.23,2262.23 3645.19,2262.23 v1(3667.81,2284.85)
  Bottom Layer w60: P9.7@3355,2105 P9.8@3355,2205
VCC5VRAW: C1.1 C2.1 C3.1 C35.1 C52.1 C53.1 C54.1 D1.K P9.5 P9.6 R1.2 R3.2 U1.2 U3.7 U4.7 | length 5004.3
  Top Layer w12: v1(3222.83,2339.56) 3222.83,2337.35 3216.87,2331.39 3252.2,2296.06 3277.47,2296.06 3304.4,2323 R3.2@3304.4,2351.37
  Top Layer w35: 4897.16,3455.19 4897.16,3325.28 4890.46,3318.58 4890.46,3223.6 4866.1,3199.24 4866.1,3068.26 4826.36,3028.52 4826.36,2973.32 4901.88,2897.79 4997.1,2897.79 5024.48,2870.41 5024.48,2722.3 ; 4901.23,3451.11 U4.7@5026.98,3451.11 ; 4910.13,3442.21 4911.02,3443.09 ; U3.7@4929.95,2640.14 4937.45,2647.64 4937.45,2660.8 4982.06,2705.41 C35.1@5041.37,2705.41
  Top Layer w50: P9.5@3255,2105 P9.6@3255,2205 ; 4348.05,3501.95 4357.5,3501.95 4403.67,3548.12 4859.13,3548.12 4882.18,3525.07 ; 4882.18,3546.57 4882.18,3525.07 ; 4910.13,3442.21 4901.23,3451.11 4897.16,3455.19 4882.18,3470.16 4882.18,3525.07 ; U3.7@4929.95,2640.14 4929.95,2663.91
  Top Layer w60: v1@2989.23,2426.27 2993.38,2422.12 3070.78,2422.12 3078.66,2430 ; P9.6@3255,2205 3188,2272 3133.1,2272 3078.66,2326.44 D1.K@3078.66,2347.65 3078.66,2430 ; v1@3703.09,2788.42 3524.17,2609.5 3157.43,2609.5 3078.66,2530.74 3078.66,2430 ; v1@4103.84,2935.36 4103.84,3004.62 4102.86,3005.59 4102.86,3022.37 4166.39,3085.89 4166.39,3320.3 4348.05,3501.95
  Bottom Layer w12: C3.1@3165.72,2427.03 3169.83,2422.92 3197.52,2395.23 3197.52,2358.68 3216.87,2339.33 v1@3226.43,2348.89 ; v1(3222.83,2339.56) v1@3222.83,2345.29
  Bottom Layer w20: R1.2@2910.29,2443.14 2983.68,2443.14 v1(2983.92,2438.38)
  Bottom Layer w60: v1@2995.59,2422.92 3169.83,2422.92 U1.2@3244.96,2422.92 ; v1@3696.15,2766.3 3755.56,2825.71 4013.08,2825.71 4102.29,2914.92 4102.29,2942.71
  other v1: 3010,2417.5 3696.62,2758.92 3711.27,2800.39 4107.45,2918.45 4096.9,2960.04
VCC_4V: C33.1 C34.1 J1.2 J6.1 R4.1 R21.2 | length 846.4
  Bottom Layer w50: J1.2@3462.69,2949.58 J1.2@3472.74,2949.58 ; R4.1@3565.88,2695.3 3565.88,2734.54 3568.22,2734.54 3568.22,2854.09 ; 3594.8,2651.46 3594.8,2671.68 3571.19,2695.3 3834.57,2695.3 3883.76,2744.49 3887.88,2740.37 J6.1@4035.67,2740.37
  Bottom Layer w55: J1.2@3472.74,2949.58 3568.22,2854.09
VCC_4VLED: C7.1 C8.1 C9.1 C10.1 J1.1 L1.2 R2.2 R4.2 R5.2 | length 732.8
  Bottom Layer w20: R2.2@2960,2605 2983.04,2628.04 3051.45,2628.04 L1.2@3062.88,2639.47
  Bottom Layer w50: L1.2@3090.45,2638.76 3408.24,2638.76 3465.79,2696.3 R5.2@3465.79,2767.85 3465.79,2846.48 J1.1@3462.69,2849.58 ; R4.2@3467.49,2694.61 R5.2@3467.49,2756.57
pads on no net: D5.1 D5.6 D7.1 D7.6 D9.1 D9.6 D11.1 D11.6 D12.1 D12.6 Fiducial1.Fiducial Fiducial2.Fiducial Fiducial3.Fiducial Fiducial4.Fiducial Fiducial5.Fiducial Fiducial6.Fiducial J3.4 J6.5 J6.17 J6.18 J6.19 J14.4 J14.5 J14.6 J14.7 J14.8 J14.9 J14.11 J14.12 J14.13 J14.14 J14.15 J14.16 J14.17 J14.18 J14.19 J14.20 P8.3 P8.4 P8.5 P8.6 P8.11 P8.12 P8.13 P8.14 P8.15 P8.16 P8.17 P8.18 P8.19 P8.20 P8.21 P8.22 P8.23 P8.24 P8.25 P8.26 P8.27 P8.28 P8.29 P8.30 P8.31 P8.32 P8.33 P8.34 P8.35 P8.36 P8.39 P8.40 P8.41 P8.42 P8.43 P8.44 P8.45 P8.46 P9.9 P9.12 P9.14 P9.15 P9.16 P9.17 P9.18 P9.23 P9.25 P9.27 P9.28 P9.29 P9.30 P9.31 P9.32 P9.33 P9.34 P9.35 P9.36 P9.37 P9.38 P9.39 P9.40 P9.41 P9.42 U10.3 U10.4 U10.12 U10.13

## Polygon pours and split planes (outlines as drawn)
GND on Signal Layer 1 "Top Layer-No Net" (solid, remove dead copper, pour order 8): 2280,2600 2280,2900 3035,2900 3035,3560 2280,3560 2280,3570 2280,3930 2282.14,3962.63 2288.52,3994.7 2299.03,4025.67 2313.49,4055 2331.66,4082.19 2353.22,4106.78 2377.81,4128.34 2405,4146.51 2434.33,4160.97 2465.3,4171.48 2497.37,4177.86 2530,4180 5180,4180 5226.13,4177.87 5271.87,4171.49 5316.83,4160.91 5360.62,4146.24 5402.87,4127.58 5443.22,4105.11 5481.32,4079.01 5516.85,4049.5 5549.5,4016.85 5579.01,3981.32 5605.11,3943.22 5627.58,3902.87 5646.24,3860.62 5660.91,3816.83 5671.49,3771.87 5677.87,3726.13 5680,3680 5680,2530 5677.87,2483.87 5671.49,2438.12 5660.91,2393.17 5646.24,2349.38 5627.58,2307.13 5605.11,2266.78 5579.01,2228.68 5549.5,2193.15 5516.85,2160.5 5481.32,2130.99 5443.22,2104.89 5402.87,2082.42 5360.62,2063.76 5316.83,2049.09 5271.87,2038.51 5226.13,2032.13 5180,2030 2530,2030 2496.68,2032.23 2463.95,2038.88 2432.4,2049.84 2402.59,2064.9 2375.05,2083.81 2350.28,2106.21 2328.72,2131.72 2310.75,2159.87 2296.7,2190.17 2286.81,2222.07 2281.25,2255 2280.04,2272.11 2280,2320 2280,2483.93
GND on Signal Layer 2 "SL2 GND" (solid, pour order 10): 2280,2600 2280,2900 3035,2900 3035,3560 2280,3560 2280,3570 2280,3930 2282.14,3962.63 2288.52,3994.7 2299.03,4025.67 2313.49,4055 2331.66,4082.19 2353.22,4106.78 2377.81,4128.34 2405,4146.51 2434.33,4160.97 2465.3,4171.48 2497.37,4177.86 2530,4180 5180,4180 5226.13,4177.87 5271.87,4171.49 5316.83,4160.91 5360.62,4146.24 5402.87,4127.58 5443.22,4105.11 5481.32,4079.01 5516.85,4049.5 5549.5,4016.85 5579.01,3981.32 5605.11,3943.22 5627.58,3902.87 5646.24,3860.62 5660.91,3816.83 5671.49,3771.87 5677.87,3726.13 5680,3680 5680,2530 5677.87,2483.87 5671.49,2438.12 5660.91,2393.17 5646.24,2349.38 5627.58,2307.13 5605.11,2266.78 5579.01,2228.68 5549.5,2193.15 5516.85,2160.5 5481.32,2130.99 5443.22,2104.89 5402.87,2082.42 5360.62,2063.76 5316.83,2049.09 5271.87,2038.51 5226.13,2032.13 5180,2030 2530,2030 2496.68,2032.23 2463.95,2038.88 2432.4,2049.84 2402.59,2064.9 2375.05,2083.81 2350.28,2106.21 2328.72,2131.72 2310.75,2159.87 2296.7,2190.17 2286.81,2222.07 2281.25,2255 2280.04,2272.11 2280,2320 2280,2483.93
GND on Top Layer "PWR TOP GND" (solid, remove dead copper, pour order 7): 3715.2,2639.04 3715.2,2548.18 3581.46,2414.45 3572.39,2405.38 3546.48,2405.38 3548.42,2403.43 3463.02,2346.07 3382.53,2335.89 3368.2,2220.98 3127.68,2254.4 3110.76,2388.37 3053.13,2527.5 3149.34,2623.7 3168.49,2642.85 3709.56,2644.65
GND on Top Layer "USB TOP GND" (solid, remove dead copper, pour order 6): 4638.11,3447.9 4628.33,3457.68 4417.05,3457.68 4417.05,3451.88 4379.22,3414.05 4379.22,3289.96 4381.38,3287.8 4381.38,3091.59 4381.38,2988.3 4390.5,2979.18 4398.54,2971.14 4621.07,2971.14 4621.07,3044.88 4625.17,3044.88 4688.86,3108.58 4625.16,3172.28 4625.16,3210.51 4625.15,3292.04 4638.11,3305
GND on Bottom Layer "PWR TOP GND" (solid, remove dead copper, pour order 9): 3599.93,2250.17 3269.62,2250.17 3218.23,2301.57 3150.95,2368.85 3137.25,2795.24 3008.97,2666.96 3008.97,2589.06 3576.33,2589.06 3616.66,2629.38 3643.22,2655.95 3643.22,2665.66 3730.68,2665.66 3733.92,2668.9 3735.21,2667.61 3735.21,2584.03 3643.22,2492.04 3643.22,2289.74

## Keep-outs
Keep-Out Layer:
  lines w20: 5646.24,3860.62 5660.91,3816.83
  lines w25: 5660.91,3816.83 5671.49,3771.87
  lines w30: 5624.9,3909.12 5643.56,3866.87 ; 5627.58,3902.87 5605.11,3943.22 5579.01,3981.32 5549.5,4016.85 5516.85,4049.5 5481.32,4079.01 5443.22,4105.11 5402.87,4127.58 5360.62,4146.24 5316.83,4160.91 5271.87,4171.49 5226.13,4177.87 5180,4180 2530,4180 2497.37,4177.86 2465.3,4171.48 2434.33,4160.97 2405,4146.51 2377.81,4128.34 2353.22,4106.78 2331.66,4082.19 2304.33,4041.29 2288.52,3994.7 2282.14,3962.63 2281.41,3951.44 2281.41,3580 3055,3580 3055,2880 2280,2880 2280,2600 ; 5671.49,3771.87 5677.87,3726.13 5680,3680 5680,2530 5677.87,2483.87 5671.49,2438.12 5660.91,2393.17 5646.24,2349.38 5627.58,2307.13 5605.11,2266.78 5579.01,2228.68 5549.5,2193.15 5516.85,2160.5 5481.32,2130.99 5443.22,2104.89 5402.87,2082.42 5360.62,2063.76 5316.83,2049.09 5271.87,2038.51 5226.13,2032.13 5180,2030 2530,2030 2496.68,2032.23 2463.95,2038.88 2432.4,2049.84 2402.59,2064.9 2375.05,2083.81 2350.28,2106.21 2328.72,2131.72 2310.75,2159.87 2296.7,2190.17 2286.81,2222.07 2281.25,2255 2280.04,2272.11 2280,2320 2280,2483.93 2280,2600 ; 2280,2600 2280,2600

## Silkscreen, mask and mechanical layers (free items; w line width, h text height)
Top Overlay:
  drawing of 3872 lines, arcs and shapes, not listed
  text "2" at 2955,4085 h40
  text "1" at 2960,3980 h40
  text "20018 REV D" at 2869.47,3753.44 h40
  text "RESET" at 5341.57,3595.58 h30
  text "2" at 2950,2185 h40
  text "1" at 2955,2080 h40
Drill Drawing:
  circle w10: c7463.56,3394.76 r15
  circle w10: c7463.56,3394.76 r25
  circle w10: c7463.56,3244.76 r25
  lines w8: 2272.76,8501.78 2272.76,10665.05 ; 5677.76,7972.06 5677.76,10665.05
  lines w10: 2272.76,8505.05 5677.76,8505.05 ; 2272.76,8605.05 5677.76,8605.05 ; 2272.76,10665.05 5677.76,10665.05 ; 2275,4177.55 5680,4177.55 ; 2275,4285 5680,4285 ; 2275,6345 5680,6345 ; 2275,6445 5680,6445 ; 2275,2025 2275,8505 5680,8505 5680,2025 2275,2025 ; 7438.56,2619.76 7488.56,2619.76 7488.56,2669.76 7438.56,2669.76 7438.56,2619.76 ; 7438.56,2782.26 7451.06,2782.26 7463.56,2769.76 7476.06,2782.26 7488.56,2782.26 7476.06,2794.76 7488.56,2807.26 7476.06,2807.26 7463.56,2819.76 7451.06,2807.26 7438.56,2807.26 7451.06,2794.76 7438.56,2782.26 ; 7438.56,2944.76 7463.56,2919.76 7488.56,2944.76 7463.56,2969.76 7438.56,2944.76 ; 7438.56,3082.26 7451.06,3082.26 7451.06,3069.76 7476.06,3069.76 7476.06,3082.26 7488.56,3082.26 7488.56,3107.26 7476.06,3107.26 7476.06,3119.76 7451.06,3119.76 7451.06,3107.26 7438.56,3107.26 7438.56,3082.26 ; 7438.56,3569.76 7488.56,3569.76 7463.56,3519.76 7438.56,3569.76 ; 7438.56,3719.76 7488.56,3719.76 7463.56,3669.76 7438.56,3719.76 ; 7438.56,3819.76 7438.56,3832.26 7451.06,3844.76 7438.56,3857.26 7438.56,3869.76 7451.06,3869.76 7463.56,3857.26 7476.06,3869.76 7488.56,3869.76 7488.56,3857.26 7476.06,3844.76 7488.56,3832.26 7488.56,3819.76 7476.06,3819.76 7463.56,3832.26 7451.06,3819.76 7438.56,3819.76 ; 7438.56,3982.26 7451.06,3982.26 7451.06,3969.76 7476.06,3969.76 7476.06,3982.26 7488.56,3982.26 7488.56,4007.26 7476.06,4007.26 7476.06,4019.76 7451.06,4019.76 7451.06,4007.26 7438.56,4007.26 7438.56,3982.26 ; 7438.56,4119.76 7463.56,4132.26 7488.56,4119.76 7476.06,4144.76 7488.56,4169.76 7463.56,4157.26 7438.56,4169.76 7451.06,4144.76 7438.56,4119.76 ; 7438.56,4269.76 7463.56,4282.26 7488.56,4269.76 7476.06,4294.76 7488.56,4319.76 7463.56,4307.26 7438.56,4319.76 7451.06,4294.76 7438.56,4269.76 ; 7448.56,3709.76 7478.56,3709.76 7463.56,3679.76 7448.56,3709.76 ; 7448.56,3987.26 7456.06,3987.26 7456.06,3979.76 7471.06,3979.76 7471.06,3987.26 7478.56,3987.26 7478.56,4002.26 7471.06,4002.26 7471.06,4009.76 7456.06,4009.76 7456.06,4002.26 7448.56,4002.26 7448.56,3987.26 ; 7448.56,4129.76 7463.56,4137.26 7478.56,4129.76 7471.06,4144.76 7478.56,4159.76 7463.56,4152.26 7448.56,4159.76 7456.06,4144.76 7448.56,4129.76
  lines w15: 7370.44,2574.76 13612.72,2574.76 ; 7370.44,4374.76 13612.72,4374.76 ; 7921.31,2424.76 7921.31,4524.76 ; 8619.13,2424.76 8619.13,4524.76 ; 9964.73,2424.76 9964.73,4524.76 ; 10470.61,2424.76 10470.61,4524.76 ; 11204.41,2424.76 11204.41,4524.76 ; 12354.07,2424.76 12354.07,4524.76 ; 7370.44,2424.76 13612.72,2424.76 13612.72,4524.76 7370.44,4524.76 7370.44,2424.76
  text "Board Copy 4" at 2637.76,9325.05 h60
  text "COPY ARTWORK" at 3512.76,9090.05 h60
  text "300 Mil Scrap, V score" at 3941.38,8539.39 h90
  text "Board Copy 3" at 2640,7165 h60
  text "COPY ARTWORK" at 3515,6930 h60
  text "300 Mil Scrap, V score" at 3943.63,6379.35 h90
  text "Board Copy 2" at 2620,5225 h60
  text "COPY ARTWORK" at 3420,4645 h60
  text "Symbol" at 7460.44,4419.76 h72
  text "Hit Count" at 7966.31,4419.76 h72
  text "Finished Hole Size" at 8664.13,4419.76 h72
  text "Plated" at 10009.73,4419.76 h72
  text "Hole Type" at 10515.61,4419.76 h72
  text "Physical Length" at 11249.41,4419.76 h72
  text "Rout Path Length" at 12399.07,4419.76 h72
  text "1" at 7966.31,4269.76 h60
  text "30.00mil (0.762mm)" at 8664.13,4269.76 h60
  text "PTH" at 10009.73,4269.76 h60
  text "Round" at 10515.61,4269.76 h60
  text "300 Mil Scrap, V score" at 4477.62,4202.39 h90
  text "1" at 7966.31,4119.76 h60
  text "32.00mil (0.813mm)" at 8664.13,4119.76 h60
  text "PTH" at 10009.73,4119.76 h60
  text "Slot" at 10515.61,4119.76 h60
  text "141.73mil (3.600mm)" at 11249.41,4119.76 h60
  text "109.73mil (2.787mm)" at 12399.07,4119.76 h60
  text "1" at 7966.31,3969.76 h60
  text "32.00mil (0.813mm)" at 8664.13,3969.76 h60
  text "PTH" at 10009.73,3969.76 h60
  text "Slot" at 10515.61,3969.76 h60
  text "142.00mil (3.607mm)" at 11249.41,3969.76 h60
  text "110.00mil (2.794mm)" at 12399.07,3969.76 h60
  text "4" at 7966.31,3819.76 h60
  text "120.00mil (3.048mm)" at 8664.13,3819.76 h60
  text "PTH" at 10009.73,3819.76 h60
  text "Round" at 10515.61,3819.76 h60
  text "8" at 7966.31,3669.76 h60
  text "35.00mil (0.889mm)" at 8664.13,3669.76 h60
  text "PTH" at 10009.73,3669.76 h60
  text "Round" at 10515.61,3669.76 h60
  text "8" at 7966.31,3519.76 h60
  text "35.43mil (0.900mm)" at 8664.13,3519.76 h60
  text "PTH" at 10009.73,3519.76 h60
  text "Round" at 10515.61,3519.76 h60
  text "12" at 7966.31,3369.76 h60
  text "38.00mil (0.965mm)" at 8664.13,3369.76 h60
  text "PTH" at 10009.73,3369.76 h60
  text "Round" at 10515.61,3369.76 h60
  text "20" at 7966.31,3219.76 h60
  text "31.50mil (0.800mm)" at 8664.13,3219.76 h60
  text "PTH" at 10009.73,3219.76 h60
  text "Round" at 10515.61,3219.76 h60
  text "20" at 7966.31,3069.76 h60
  text "65.00mil (1.651mm)" at 8664.13,3069.76 h60
  text "PTH" at 10009.73,3069.76 h60
  text "Round" at 10515.61,3069.76 h60
  text "24" at 7966.31,2919.76 h60
  text "32.00mil (0.813mm)" at 8664.13,2919.76 h60
  text "PTH" at 10009.73,2919.76 h60
  text "Round" at 10515.61,2919.76 h60
  text "92" at 7966.31,2769.76 h60
  text "40.00mil (1.016mm)" at 8664.13,2769.76 h60
  text "PTH" at 10009.73,2769.76 h60
  text "Round" at 10515.61,2769.76 h60
  text "320" at 7966.31,2619.76 h60
  text "15.00mil (0.381mm)" at 8664.13,2619.76 h60
  text "PTH" at 10009.73,2619.76 h60
  text "Round" at 10515.61,2619.76 h60
  text "511 Total" at 7966.31,2469.76 h60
